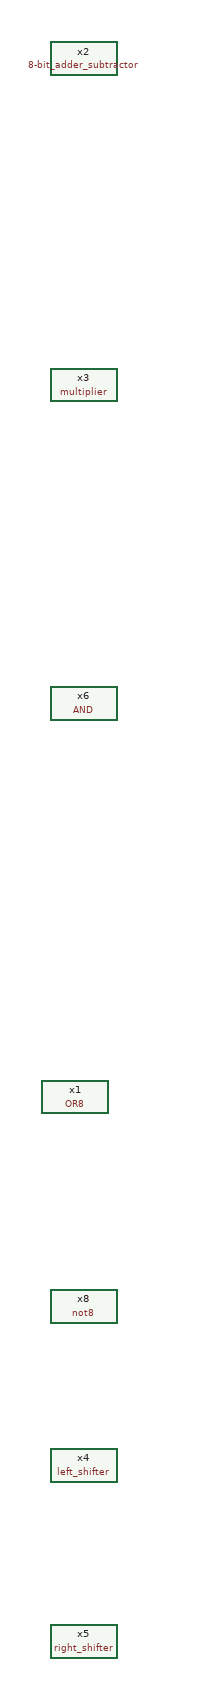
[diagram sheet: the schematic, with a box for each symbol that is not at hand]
v {xschem version=3.4.6 file_version=1.2}
G {}
K {}
V {}
S {}
E {}
C {SUBTRACTOR/8-bit_adder_subtractor.sym} 220 430 0 0 {name=x2}
C {MULTIPLIER/multiplier.sym} 220 820 0 0 {name=x3}
C {SHIFTER/left_shifter.sym} 220 2110 0 0 {name=x4}
C {SHIFTER/right_shifter.sym} 220 2320 0 0 {name=x5}
C {AND8/AND.sym} 220 1200 0 0 {name=x6}
C {NOT/not8.sym} 220 1920 0 0 {name=x8 VSS=VSS VDD=VDD}
C {OR/OR8.sym} 210 1670 0 0 {name=x1}
